VERSION 5.8 ;
BUSBITCHARS "[]" ;
DIVIDERCHAR "/" ;
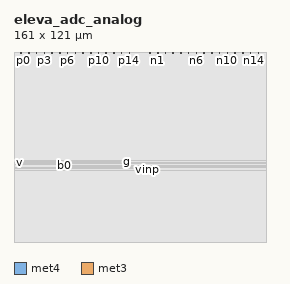
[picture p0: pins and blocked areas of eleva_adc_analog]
MACRO eleva_adc_analog
  CLASS BLOCK ;
  ORIGIN 0 0 ;
  SIZE 161.000 BY 121.000 ;
  SYMMETRY X Y ;
  PIN vinp
    DIRECTION INPUT ;
    USE SIGNAL ;
    PORT
      LAYER met4 ;
        RECT 85.125 46.265 85.475 46.615 ;
    END
  END vinp
  PIN vinn
    DIRECTION INPUT ;
    USE SIGNAL ;
    PORT
      LAYER met4 ;
        RECT 83.925 47.255 84.275 47.605 ;
    END
  END vinn
  PIN b0
    DIRECTION INPUT ;
    USE SIGNAL ;
    PORT
      LAYER met4 ;
        RECT 32.140 48.245 32.490 48.595 ;
    END
  END b0
  PIN b1
    DIRECTION INPUT ;
    USE SIGNAL ;
    PORT
      LAYER met4 ;
        RECT 35.170 49.235 35.520 49.585 ;
    END
  END b1
  PIN v
    DIRECTION INOUT ;
    USE POWER ;
    PORT
      LAYER met4 ;
        RECT 2.575 50.225 2.925 50.575 ;
    END
  END v
  PIN g
    DIRECTION INOUT ;
    USE GROUND ;
    PORT
      LAYER met4 ;
        RECT 71.825 51.215 72.175 51.565 ;
    END
  END g
  PIN p0
    DIRECTION OUTPUT ;
    USE SIGNAL ;
    PORT
      LAYER met3 ;
        RECT 4.395 120.275 4.745 120.625 ;
    END
  END p0
  PIN p1
    DIRECTION OUTPUT ;
    USE SIGNAL ;
    PORT
      LAYER met3 ;
        RECT 9.320 120.275 9.670 120.625 ;
    END
  END p1
  PIN p2
    DIRECTION OUTPUT ;
    USE SIGNAL ;
    PORT
      LAYER met3 ;
        RECT 14.245 120.275 14.595 120.625 ;
    END
  END p2
  PIN p3
    DIRECTION OUTPUT ;
    USE SIGNAL ;
    PORT
      LAYER met3 ;
        RECT 19.170 120.275 19.520 120.625 ;
    END
  END p3
  PIN p4
    DIRECTION OUTPUT ;
    USE SIGNAL ;
    PORT
      LAYER met3 ;
        RECT 24.095 120.275 24.445 120.625 ;
    END
  END p4
  PIN p5
    DIRECTION OUTPUT ;
    USE SIGNAL ;
    PORT
      LAYER met3 ;
        RECT 29.020 120.275 29.370 120.625 ;
    END
  END p5
  PIN p6
    DIRECTION OUTPUT ;
    USE SIGNAL ;
    PORT
      LAYER met3 ;
        RECT 33.945 120.275 34.295 120.625 ;
    END
  END p6
  PIN p7
    DIRECTION OUTPUT ;
    USE SIGNAL ;
    PORT
      LAYER met3 ;
        RECT 38.870 120.275 39.220 120.625 ;
    END
  END p7
  PIN p8
    DIRECTION OUTPUT ;
    USE SIGNAL ;
    PORT
      LAYER met3 ;
        RECT 43.795 120.275 44.145 120.625 ;
    END
  END p8
  PIN p9
    DIRECTION OUTPUT ;
    USE SIGNAL ;
    PORT
      LAYER met3 ;
        RECT 48.720 120.275 49.070 120.625 ;
    END
  END p9
  PIN p10
    DIRECTION OUTPUT ;
    USE SIGNAL ;
    PORT
      LAYER met3 ;
        RECT 53.645 120.275 53.995 120.625 ;
    END
  END p10
  PIN p11
    DIRECTION OUTPUT ;
    USE SIGNAL ;
    PORT
      LAYER met3 ;
        RECT 58.570 120.275 58.920 120.625 ;
    END
  END p11
  PIN p12
    DIRECTION OUTPUT ;
    USE SIGNAL ;
    PORT
      LAYER met3 ;
        RECT 63.495 120.275 63.845 120.625 ;
    END
  END p12
  PIN p13
    DIRECTION OUTPUT ;
    USE SIGNAL ;
    PORT
      LAYER met3 ;
        RECT 68.420 120.275 68.770 120.625 ;
    END
  END p13
  PIN p14
    DIRECTION OUTPUT ;
    USE SIGNAL ;
    PORT
      LAYER met3 ;
        RECT 73.345 120.275 73.695 120.625 ;
    END
  END p14
  PIN n0
    DIRECTION OUTPUT ;
    USE SIGNAL ;
    PORT
      LAYER met3 ;
        RECT 86.445 120.275 86.795 120.625 ;
    END
  END n0
  PIN n1
    DIRECTION OUTPUT ;
    USE SIGNAL ;
    PORT
      LAYER met3 ;
        RECT 91.370 120.275 91.720 120.625 ;
    END
  END n1
  PIN n2
    DIRECTION OUTPUT ;
    USE SIGNAL ;
    PORT
      LAYER met3 ;
        RECT 96.295 120.275 96.645 120.625 ;
    END
  END n2
  PIN n3
    DIRECTION OUTPUT ;
    USE SIGNAL ;
    PORT
      LAYER met3 ;
        RECT 101.220 120.275 101.570 120.625 ;
    END
  END n3
  PIN n4
    DIRECTION OUTPUT ;
    USE SIGNAL ;
    PORT
      LAYER met3 ;
        RECT 106.145 120.275 106.495 120.625 ;
    END
  END n4
  PIN n5
    DIRECTION OUTPUT ;
    USE SIGNAL ;
    PORT
      LAYER met3 ;
        RECT 111.070 120.275 111.420 120.625 ;
    END
  END n5
  PIN n6
    DIRECTION OUTPUT ;
    USE SIGNAL ;
    PORT
      LAYER met3 ;
        RECT 115.995 120.275 116.345 120.625 ;
    END
  END n6
  PIN n7
    DIRECTION OUTPUT ;
    USE SIGNAL ;
    PORT
      LAYER met3 ;
        RECT 120.920 120.275 121.270 120.625 ;
    END
  END n7
  PIN n8
    DIRECTION OUTPUT ;
    USE SIGNAL ;
    PORT
      LAYER met3 ;
        RECT 125.845 120.275 126.195 120.625 ;
    END
  END n8
  PIN n9
    DIRECTION OUTPUT ;
    USE SIGNAL ;
    PORT
      LAYER met3 ;
        RECT 130.770 120.275 131.120 120.625 ;
    END
  END n9
  PIN n10
    DIRECTION OUTPUT ;
    USE SIGNAL ;
    PORT
      LAYER met3 ;
        RECT 135.695 120.275 136.045 120.625 ;
    END
  END n10
  PIN n11
    DIRECTION OUTPUT ;
    USE SIGNAL ;
    PORT
      LAYER met3 ;
        RECT 140.620 120.275 140.970 120.625 ;
    END
  END n11
  PIN n12
    DIRECTION OUTPUT ;
    USE SIGNAL ;
    PORT
      LAYER met3 ;
        RECT 145.545 120.275 145.895 120.625 ;
    END
  END n12
  PIN n13
    DIRECTION OUTPUT ;
    USE SIGNAL ;
    PORT
      LAYER met3 ;
        RECT 150.470 120.275 150.820 120.625 ;
    END
  END n13
  PIN n14
    DIRECTION OUTPUT ;
    USE SIGNAL ;
    PORT
      LAYER met3 ;
        RECT 155.395 120.275 155.745 120.625 ;
    END
  END n14
  OBS
    LAYER li1 ;
      RECT 0.000 0.000 161.000 121.000 ;
    LAYER met1 ;
      RECT 0.000 0.000 161.000 121.000 ;
    LAYER met2 ;
      RECT 0.000 0.000 161.000 121.000 ;
    LAYER met3 ;
      RECT 0.000 0.000 161.000 119.625 ;
      RECT 0.000 119.625 3.745 121.000 ;
      RECT 5.395 119.625 8.670 121.000 ;
      RECT 10.320 119.625 13.595 121.000 ;
      RECT 15.245 119.625 18.520 121.000 ;
      RECT 20.170 119.625 23.445 121.000 ;
      RECT 25.095 119.625 28.370 121.000 ;
      RECT 30.020 119.625 33.295 121.000 ;
      RECT 34.945 119.625 38.220 121.000 ;
      RECT 39.870 119.625 43.145 121.000 ;
      RECT 44.795 119.625 48.070 121.000 ;
      RECT 49.720 119.625 52.995 121.000 ;
      RECT 54.645 119.625 57.920 121.000 ;
      RECT 59.570 119.625 62.845 121.000 ;
      RECT 64.495 119.625 67.770 121.000 ;
      RECT 69.420 119.625 72.695 121.000 ;
      RECT 74.345 119.625 85.795 121.000 ;
      RECT 87.445 119.625 90.720 121.000 ;
      RECT 92.370 119.625 95.645 121.000 ;
      RECT 97.295 119.625 100.570 121.000 ;
      RECT 102.220 119.625 105.495 121.000 ;
      RECT 107.145 119.625 110.420 121.000 ;
      RECT 112.070 119.625 115.345 121.000 ;
      RECT 116.995 119.625 120.270 121.000 ;
      RECT 121.920 119.625 125.195 121.000 ;
      RECT 126.845 119.625 130.120 121.000 ;
      RECT 131.770 119.625 135.045 121.000 ;
      RECT 136.695 119.625 139.970 121.000 ;
      RECT 141.620 119.625 144.895 121.000 ;
      RECT 146.545 119.625 149.820 121.000 ;
      RECT 151.470 119.625 154.745 121.000 ;
      RECT 156.395 119.625 161.000 121.000 ;
    LAYER met4 ;
      RECT 0.000 0.000 161.000 45.615 ;
      RECT 0.000 45.615 84.475 46.605 ;
      RECT 86.125 45.615 161.000 47.265 ;
      RECT 0.000 46.605 83.275 47.595 ;
      RECT 33.140 47.595 83.275 48.255 ;
      RECT 84.925 47.265 161.000 48.255 ;
      RECT 33.140 48.255 161.000 48.585 ;
      RECT 0.000 47.595 31.490 49.245 ;
      RECT 33.140 48.585 34.520 49.245 ;
      RECT 0.000 49.245 34.520 49.575 ;
      RECT 3.575 49.575 34.520 50.235 ;
      RECT 36.170 48.585 161.000 50.235 ;
      RECT 3.575 50.235 161.000 50.565 ;
      RECT 0.000 49.575 1.925 51.225 ;
      RECT 3.575 50.565 71.175 51.225 ;
      RECT 0.000 51.225 71.175 52.215 ;
      RECT 72.825 50.565 161.000 52.215 ;
      RECT 0.000 52.215 161.000 121.000 ;
  END
END eleva_adc_analog
END LIBRARY
